VERSION 5.8 ;
BUSBITCHARS "[]" ;
DIVIDERCHAR "/" ;
UNITS
    DATABASE MICRONS 1000 ;
END UNITS

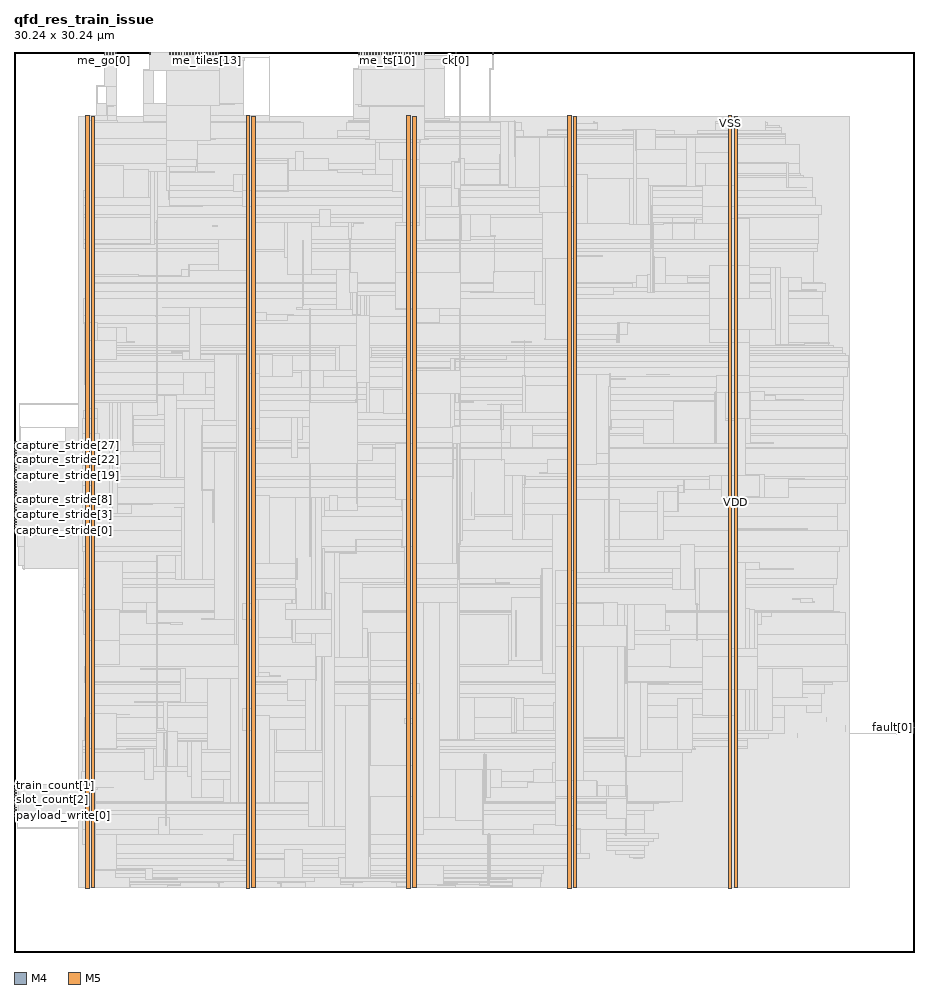
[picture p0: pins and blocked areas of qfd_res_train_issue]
MACRO qfd_res_train_issue
  FOREIGN qfd_res_train_issue 0 0 ;
  CLASS BLOCK ;
  SIZE 30.24 BY 30.24 ;
  PIN capture_stride[0]
    DIRECTION OUTPUT ;
    USE SIGNAL ;
    PORT
      LAYER M4 ;
        RECT  0 14.16 0.084 14.184 ;
    END
  END capture_stride[0]
  PIN capture_stride[10]
    DIRECTION OUTPUT ;
    USE SIGNAL ;
    PORT
      LAYER M4 ;
        RECT  0 15.12 0.084 15.144 ;
    END
  END capture_stride[10]
  PIN capture_stride[11]
    DIRECTION OUTPUT ;
    USE SIGNAL ;
    PORT
      LAYER M4 ;
        RECT  0 15.216 0.084 15.24 ;
    END
  END capture_stride[11]
  PIN capture_stride[12]
    DIRECTION OUTPUT ;
    USE SIGNAL ;
    PORT
      LAYER M4 ;
        RECT  0 15.312 0.084 15.336 ;
    END
  END capture_stride[12]
  PIN capture_stride[13]
    DIRECTION OUTPUT ;
    USE SIGNAL ;
    PORT
      LAYER M4 ;
        RECT  0 15.408 0.084 15.432 ;
    END
  END capture_stride[13]
  PIN capture_stride[14]
    DIRECTION OUTPUT ;
    USE SIGNAL ;
    PORT
      LAYER M4 ;
        RECT  0 15.504 0.084 15.528 ;
    END
  END capture_stride[14]
  PIN capture_stride[15]
    DIRECTION OUTPUT ;
    USE SIGNAL ;
    PORT
      LAYER M4 ;
        RECT  0 15.6 0.084 15.624 ;
    END
  END capture_stride[15]
  PIN capture_stride[16]
    DIRECTION OUTPUT ;
    USE SIGNAL ;
    PORT
      LAYER M4 ;
        RECT  0 15.696 0.084 15.72 ;
    END
  END capture_stride[16]
  PIN capture_stride[17]
    DIRECTION OUTPUT ;
    USE SIGNAL ;
    PORT
      LAYER M4 ;
        RECT  0 15.792 0.084 15.816 ;
    END
  END capture_stride[17]
  PIN capture_stride[18]
    DIRECTION OUTPUT ;
    USE SIGNAL ;
    PORT
      LAYER M4 ;
        RECT  0 15.888 0.084 15.912 ;
    END
  END capture_stride[18]
  PIN capture_stride[19]
    DIRECTION OUTPUT ;
    USE SIGNAL ;
    PORT
      LAYER M4 ;
        RECT  0 15.984 0.084 16.008 ;
    END
  END capture_stride[19]
  PIN capture_stride[1]
    DIRECTION OUTPUT ;
    USE SIGNAL ;
    PORT
      LAYER M4 ;
        RECT  0 14.256 0.084 14.28 ;
    END
  END capture_stride[1]
  PIN capture_stride[20]
    DIRECTION OUTPUT ;
    USE SIGNAL ;
    PORT
      LAYER M4 ;
        RECT  0 16.08 0.084 16.104 ;
    END
  END capture_stride[20]
  PIN capture_stride[21]
    DIRECTION OUTPUT ;
    USE SIGNAL ;
    PORT
      LAYER M4 ;
        RECT  0 16.176 0.084 16.2 ;
    END
  END capture_stride[21]
  PIN capture_stride[22]
    DIRECTION OUTPUT ;
    USE SIGNAL ;
    PORT
      LAYER M4 ;
        RECT  0 16.272 0.084 16.296 ;
    END
  END capture_stride[22]
  PIN capture_stride[23]
    DIRECTION OUTPUT ;
    USE SIGNAL ;
    PORT
      LAYER M4 ;
        RECT  0 16.368 0.084 16.392 ;
    END
  END capture_stride[23]
  PIN capture_stride[24]
    DIRECTION OUTPUT ;
    USE SIGNAL ;
    PORT
      LAYER M4 ;
        RECT  0 16.464 0.084 16.488 ;
    END
  END capture_stride[24]
  PIN capture_stride[25]
    DIRECTION OUTPUT ;
    USE SIGNAL ;
    PORT
      LAYER M4 ;
        RECT  0 16.56 0.084 16.584 ;
    END
  END capture_stride[25]
  PIN capture_stride[26]
    DIRECTION OUTPUT ;
    USE SIGNAL ;
    PORT
      LAYER M4 ;
        RECT  0 16.656 0.084 16.68 ;
    END
  END capture_stride[26]
  PIN capture_stride[27]
    DIRECTION OUTPUT ;
    USE SIGNAL ;
    PORT
      LAYER M4 ;
        RECT  0 16.752 0.084 16.776 ;
    END
  END capture_stride[27]
  PIN capture_stride[28]
    DIRECTION OUTPUT ;
    USE SIGNAL ;
    PORT
      LAYER M4 ;
        RECT  0 16.848 0.084 16.872 ;
    END
  END capture_stride[28]
  PIN capture_stride[29]
    DIRECTION OUTPUT ;
    USE SIGNAL ;
    PORT
      LAYER M4 ;
        RECT  0 16.944 0.084 16.968 ;
    END
  END capture_stride[29]
  PIN capture_stride[2]
    DIRECTION OUTPUT ;
    USE SIGNAL ;
    PORT
      LAYER M4 ;
        RECT  0 14.352 0.084 14.376 ;
    END
  END capture_stride[2]
  PIN capture_stride[30]
    DIRECTION OUTPUT ;
    USE SIGNAL ;
    PORT
      LAYER M4 ;
        RECT  0 17.04 0.084 17.064 ;
    END
  END capture_stride[30]
  PIN capture_stride[31]
    DIRECTION OUTPUT ;
    USE SIGNAL ;
    PORT
      LAYER M4 ;
        RECT  0 17.136 0.084 17.16 ;
    END
  END capture_stride[31]
  PIN capture_stride[3]
    DIRECTION OUTPUT ;
    USE SIGNAL ;
    PORT
      LAYER M4 ;
        RECT  0 14.448 0.084 14.472 ;
    END
  END capture_stride[3]
  PIN capture_stride[4]
    DIRECTION OUTPUT ;
    USE SIGNAL ;
    PORT
      LAYER M4 ;
        RECT  0 14.544 0.084 14.568 ;
    END
  END capture_stride[4]
  PIN capture_stride[5]
    DIRECTION OUTPUT ;
    USE SIGNAL ;
    PORT
      LAYER M4 ;
        RECT  0 14.64 0.084 14.664 ;
    END
  END capture_stride[5]
  PIN capture_stride[6]
    DIRECTION OUTPUT ;
    USE SIGNAL ;
    PORT
      LAYER M4 ;
        RECT  0 14.736 0.084 14.76 ;
    END
  END capture_stride[6]
  PIN capture_stride[7]
    DIRECTION OUTPUT ;
    USE SIGNAL ;
    PORT
      LAYER M4 ;
        RECT  0 14.832 0.084 14.856 ;
    END
  END capture_stride[7]
  PIN capture_stride[8]
    DIRECTION OUTPUT ;
    USE SIGNAL ;
    PORT
      LAYER M4 ;
        RECT  0 14.928 0.084 14.952 ;
    END
  END capture_stride[8]
  PIN capture_stride[9]
    DIRECTION OUTPUT ;
    USE SIGNAL ;
    PORT
      LAYER M4 ;
        RECT  0 15.024 0.084 15.048 ;
    END
  END capture_stride[9]
  PIN ck[0]
    DIRECTION INPUT ;
    USE SIGNAL ;
    PORT
      LAYER M5 ;
        RECT  14.832 30.156 14.856 30.24 ;
    END
  END ck[0]
  PIN fault[0]
    DIRECTION OUTPUT ;
    USE SIGNAL ;
    PORT
      LAYER M4 ;
        RECT  30.156 7.536 30.24 7.56 ;
    END
  END fault[0]
  PIN me_go[0]
    DIRECTION INPUT ;
    USE SIGNAL ;
    PORT
      LAYER M5 ;
        RECT  3.024 30.156 3.048 30.24 ;
    END
  END me_go[0]
  PIN me_oen[0]
    DIRECTION INPUT ;
    USE SIGNAL ;
    PORT
      LAYER M5 ;
        RECT  4.56 30.156 4.584 30.24 ;
    END
  END me_oen[0]
  PIN me_split[0]
    DIRECTION INPUT ;
    USE SIGNAL ;
    PORT
      LAYER M5 ;
        RECT  3.12 30.156 3.144 30.24 ;
    END
  END me_split[0]
  PIN me_split[1]
    DIRECTION INPUT ;
    USE SIGNAL ;
    PORT
      LAYER M5 ;
        RECT  3.216 30.156 3.24 30.24 ;
    END
  END me_split[1]
  PIN me_split[2]
    DIRECTION INPUT ;
    USE SIGNAL ;
    PORT
      LAYER M5 ;
        RECT  3.312 30.156 3.336 30.24 ;
    END
  END me_split[2]
  PIN me_split[3]
    DIRECTION INPUT ;
    USE SIGNAL ;
    PORT
      LAYER M5 ;
        RECT  3.408 30.156 3.432 30.24 ;
    END
  END me_split[3]
  PIN me_tiles[0]
    DIRECTION INPUT ;
    USE SIGNAL ;
    PORT
      LAYER M5 ;
        RECT  5.232 30.156 5.256 30.24 ;
    END
  END me_tiles[0]
  PIN me_tiles[10]
    DIRECTION INPUT ;
    USE SIGNAL ;
    PORT
      LAYER M5 ;
        RECT  6.192 30.156 6.216 30.24 ;
    END
  END me_tiles[10]
  PIN me_tiles[11]
    DIRECTION INPUT ;
    USE SIGNAL ;
    PORT
      LAYER M5 ;
        RECT  6.288 30.156 6.312 30.24 ;
    END
  END me_tiles[11]
  PIN me_tiles[12]
    DIRECTION INPUT ;
    USE SIGNAL ;
    PORT
      LAYER M5 ;
        RECT  6.384 30.156 6.408 30.24 ;
    END
  END me_tiles[12]
  PIN me_tiles[13]
    DIRECTION INPUT ;
    USE SIGNAL ;
    PORT
      LAYER M5 ;
        RECT  6.48 30.156 6.504 30.24 ;
    END
  END me_tiles[13]
  PIN me_tiles[14]
    DIRECTION INPUT ;
    USE SIGNAL ;
    PORT
      LAYER M5 ;
        RECT  6.576 30.156 6.6 30.24 ;
    END
  END me_tiles[14]
  PIN me_tiles[15]
    DIRECTION INPUT ;
    USE SIGNAL ;
    PORT
      LAYER M5 ;
        RECT  6.672 30.156 6.696 30.24 ;
    END
  END me_tiles[15]
  PIN me_tiles[16]
    DIRECTION INPUT ;
    USE SIGNAL ;
    PORT
      LAYER M5 ;
        RECT  6.768 30.156 6.792 30.24 ;
    END
  END me_tiles[16]
  PIN me_tiles[17]
    DIRECTION INPUT ;
    USE SIGNAL ;
    PORT
      LAYER M5 ;
        RECT  6.864 30.156 6.888 30.24 ;
    END
  END me_tiles[17]
  PIN me_tiles[1]
    DIRECTION INPUT ;
    USE SIGNAL ;
    PORT
      LAYER M5 ;
        RECT  5.328 30.156 5.352 30.24 ;
    END
  END me_tiles[1]
  PIN me_tiles[2]
    DIRECTION INPUT ;
    USE SIGNAL ;
    PORT
      LAYER M5 ;
        RECT  5.424 30.156 5.448 30.24 ;
    END
  END me_tiles[2]
  PIN me_tiles[3]
    DIRECTION INPUT ;
    USE SIGNAL ;
    PORT
      LAYER M5 ;
        RECT  5.52 30.156 5.544 30.24 ;
    END
  END me_tiles[3]
  PIN me_tiles[4]
    DIRECTION INPUT ;
    USE SIGNAL ;
    PORT
      LAYER M5 ;
        RECT  5.616 30.156 5.64 30.24 ;
    END
  END me_tiles[4]
  PIN me_tiles[5]
    DIRECTION INPUT ;
    USE SIGNAL ;
    PORT
      LAYER M5 ;
        RECT  5.712 30.156 5.736 30.24 ;
    END
  END me_tiles[5]
  PIN me_tiles[6]
    DIRECTION INPUT ;
    USE SIGNAL ;
    PORT
      LAYER M5 ;
        RECT  5.808 30.156 5.832 30.24 ;
    END
  END me_tiles[6]
  PIN me_tiles[7]
    DIRECTION INPUT ;
    USE SIGNAL ;
    PORT
      LAYER M5 ;
        RECT  5.904 30.156 5.928 30.24 ;
    END
  END me_tiles[7]
  PIN me_tiles[8]
    DIRECTION INPUT ;
    USE SIGNAL ;
    PORT
      LAYER M5 ;
        RECT  6 30.156 6.024 30.24 ;
    END
  END me_tiles[8]
  PIN me_tiles[9]
    DIRECTION INPUT ;
    USE SIGNAL ;
    PORT
      LAYER M5 ;
        RECT  6.096 30.156 6.12 30.24 ;
    END
  END me_tiles[9]
  PIN me_ts[0]
    DIRECTION INPUT ;
    USE SIGNAL ;
    PORT
      LAYER M5 ;
        RECT  11.568 30.156 11.592 30.24 ;
    END
  END me_ts[0]
  PIN me_ts[10]
    DIRECTION INPUT ;
    USE SIGNAL ;
    PORT
      LAYER M5 ;
        RECT  12.528 30.156 12.552 30.24 ;
    END
  END me_ts[10]
  PIN me_ts[11]
    DIRECTION INPUT ;
    USE SIGNAL ;
    PORT
      LAYER M5 ;
        RECT  12.624 30.156 12.648 30.24 ;
    END
  END me_ts[11]
  PIN me_ts[12]
    DIRECTION INPUT ;
    USE SIGNAL ;
    PORT
      LAYER M5 ;
        RECT  12.72 30.156 12.744 30.24 ;
    END
  END me_ts[12]
  PIN me_ts[13]
    DIRECTION INPUT ;
    USE SIGNAL ;
    PORT
      LAYER M5 ;
        RECT  12.816 30.156 12.84 30.24 ;
    END
  END me_ts[13]
  PIN me_ts[14]
    DIRECTION INPUT ;
    USE SIGNAL ;
    PORT
      LAYER M5 ;
        RECT  12.912 30.156 12.936 30.24 ;
    END
  END me_ts[14]
  PIN me_ts[15]
    DIRECTION INPUT ;
    USE SIGNAL ;
    PORT
      LAYER M5 ;
        RECT  13.008 30.156 13.032 30.24 ;
    END
  END me_ts[15]
  PIN me_ts[16]
    DIRECTION INPUT ;
    USE SIGNAL ;
    PORT
      LAYER M5 ;
        RECT  13.104 30.156 13.128 30.24 ;
    END
  END me_ts[16]
  PIN me_ts[17]
    DIRECTION INPUT ;
    USE SIGNAL ;
    PORT
      LAYER M5 ;
        RECT  13.2 30.156 13.224 30.24 ;
    END
  END me_ts[17]
  PIN me_ts[18]
    DIRECTION INPUT ;
    USE SIGNAL ;
    PORT
      LAYER M5 ;
        RECT  13.296 30.156 13.32 30.24 ;
    END
  END me_ts[18]
  PIN me_ts[19]
    DIRECTION INPUT ;
    USE SIGNAL ;
    PORT
      LAYER M5 ;
        RECT  13.392 30.156 13.416 30.24 ;
    END
  END me_ts[19]
  PIN me_ts[1]
    DIRECTION INPUT ;
    USE SIGNAL ;
    PORT
      LAYER M5 ;
        RECT  11.664 30.156 11.688 30.24 ;
    END
  END me_ts[1]
  PIN me_ts[20]
    DIRECTION INPUT ;
    USE SIGNAL ;
    PORT
      LAYER M5 ;
        RECT  13.488 30.156 13.512 30.24 ;
    END
  END me_ts[20]
  PIN me_ts[21]
    DIRECTION INPUT ;
    USE SIGNAL ;
    PORT
      LAYER M5 ;
        RECT  13.584 30.156 13.608 30.24 ;
    END
  END me_ts[21]
  PIN me_ts[22]
    DIRECTION INPUT ;
    USE SIGNAL ;
    PORT
      LAYER M5 ;
        RECT  13.68 30.156 13.704 30.24 ;
    END
  END me_ts[22]
  PIN me_ts[23]
    DIRECTION INPUT ;
    USE SIGNAL ;
    PORT
      LAYER M5 ;
        RECT  13.776 30.156 13.8 30.24 ;
    END
  END me_ts[23]
  PIN me_ts[2]
    DIRECTION INPUT ;
    USE SIGNAL ;
    PORT
      LAYER M5 ;
        RECT  11.76 30.156 11.784 30.24 ;
    END
  END me_ts[2]
  PIN me_ts[3]
    DIRECTION INPUT ;
    USE SIGNAL ;
    PORT
      LAYER M5 ;
        RECT  11.856 30.156 11.88 30.24 ;
    END
  END me_ts[3]
  PIN me_ts[4]
    DIRECTION INPUT ;
    USE SIGNAL ;
    PORT
      LAYER M5 ;
        RECT  11.952 30.156 11.976 30.24 ;
    END
  END me_ts[4]
  PIN me_ts[5]
    DIRECTION INPUT ;
    USE SIGNAL ;
    PORT
      LAYER M5 ;
        RECT  12.048 30.156 12.072 30.24 ;
    END
  END me_ts[5]
  PIN me_ts[6]
    DIRECTION INPUT ;
    USE SIGNAL ;
    PORT
      LAYER M5 ;
        RECT  12.144 30.156 12.168 30.24 ;
    END
  END me_ts[6]
  PIN me_ts[7]
    DIRECTION INPUT ;
    USE SIGNAL ;
    PORT
      LAYER M5 ;
        RECT  12.24 30.156 12.264 30.24 ;
    END
  END me_ts[7]
  PIN me_ts[8]
    DIRECTION INPUT ;
    USE SIGNAL ;
    PORT
      LAYER M5 ;
        RECT  12.336 30.156 12.36 30.24 ;
    END
  END me_ts[8]
  PIN me_ts[9]
    DIRECTION INPUT ;
    USE SIGNAL ;
    PORT
      LAYER M5 ;
        RECT  12.432 30.156 12.456 30.24 ;
    END
  END me_ts[9]
  PIN payload_write[0]
    DIRECTION OUTPUT ;
    USE SIGNAL ;
    PORT
      LAYER M4 ;
        RECT  0 4.56 0.084 4.584 ;
    END
  END payload_write[0]
  PIN rst_n[0]
    DIRECTION INPUT ;
    USE SIGNAL ;
    PORT
      LAYER M5 ;
        RECT  16.08 30.156 16.104 30.24 ;
    END
  END rst_n[0]
  PIN slot_count[0]
    DIRECTION OUTPUT ;
    USE SIGNAL ;
    PORT
      LAYER M4 ;
        RECT  0 4.656 0.084 4.68 ;
    END
  END slot_count[0]
  PIN slot_count[1]
    DIRECTION OUTPUT ;
    USE SIGNAL ;
    PORT
      LAYER M4 ;
        RECT  0 4.752 0.084 4.776 ;
    END
  END slot_count[1]
  PIN slot_count[2]
    DIRECTION OUTPUT ;
    USE SIGNAL ;
    PORT
      LAYER M4 ;
        RECT  0 4.848 0.084 4.872 ;
    END
  END slot_count[2]
  PIN slot_count[3]
    DIRECTION OUTPUT ;
    USE SIGNAL ;
    PORT
      LAYER M4 ;
        RECT  0 4.944 0.084 4.968 ;
    END
  END slot_count[3]
  PIN tag_last[0]
    DIRECTION INPUT ;
    USE SIGNAL ;
    PORT
      LAYER M4 ;
        RECT  0 5.04 0.084 5.064 ;
    END
  END tag_last[0]
  PIN tag_v[0]
    DIRECTION INPUT ;
    USE SIGNAL ;
    PORT
      LAYER M4 ;
        RECT  0 5.136 0.084 5.16 ;
    END
  END tag_v[0]
  PIN train_count[0]
    DIRECTION OUTPUT ;
    USE SIGNAL ;
    PORT
      LAYER M4 ;
        RECT  0 5.232 0.084 5.256 ;
    END
  END train_count[0]
  PIN train_count[1]
    DIRECTION OUTPUT ;
    USE SIGNAL ;
    PORT
      LAYER M4 ;
        RECT  0 5.328 0.084 5.352 ;
    END
  END train_count[1]
  PIN train_count[2]
    DIRECTION OUTPUT ;
    USE SIGNAL ;
    PORT
      LAYER M4 ;
        RECT  0 5.424 0.084 5.448 ;
    END
  END train_count[2]
  PIN train_count[3]
    DIRECTION OUTPUT ;
    USE SIGNAL ;
    PORT
      LAYER M4 ;
        RECT  0 5.52 0.084 5.544 ;
    END
  END train_count[3]
  PIN train_start[0]
    DIRECTION OUTPUT ;
    USE SIGNAL ;
    PORT
      LAYER M4 ;
        RECT  0 5.616 0.084 5.64 ;
    END
  END train_start[0]
  PIN VDD
    DIRECTION INOUT ;
    USE POWER ;
    PORT
      LAYER M5 ;
        RECT  24.192 2.151 24.312 28.089 ;
        RECT  18.792 2.151 18.912 28.089 ;
        RECT  13.392 2.151 13.512 28.089 ;
        RECT  7.992 2.151 8.112 28.089 ;
        RECT  2.592 2.151 2.712 28.089 ;
    END
  END VDD
  PIN VSS
    DIRECTION INOUT ;
    USE GROUND ;
    PORT
      LAYER M5 ;
        RECT  24 2.137 24.12 28.103 ;
        RECT  18.6 2.137 18.72 28.103 ;
        RECT  13.2 2.137 13.32 28.103 ;
        RECT  7.8 2.137 7.92 28.103 ;
        RECT  2.4 2.137 2.52 28.103 ;
    END
  END VSS
  OBS
    LAYER RVTN ;
     RECT  2.16 2.16 28.08 2.295 ;
     RECT  2.16 2.565 28.08 2.835 ;
     RECT  2.16 3.105 28.08 3.375 ;
     RECT  2.16 3.645 28.08 3.915 ;
     RECT  2.16 4.185 28.08 4.455 ;
     RECT  2.16 4.725 28.08 4.995 ;
     RECT  2.16 5.265 28.08 5.535 ;
     RECT  2.16 5.805 28.08 6.075 ;
     RECT  2.16 6.345 28.08 6.615 ;
     RECT  2.16 6.885 28.08 7.155 ;
     RECT  2.16 7.425 28.08 7.695 ;
     RECT  2.16 7.965 28.08 8.235 ;
     RECT  2.16 8.505 28.08 8.775 ;
     RECT  2.16 9.045 28.08 9.315 ;
     RECT  2.16 9.585 28.08 9.855 ;
     RECT  2.16 10.125 28.08 10.395 ;
     RECT  2.16 10.665 28.08 10.935 ;
     RECT  2.16 11.205 28.08 11.475 ;
     RECT  2.16 11.745 28.08 12.015 ;
     RECT  2.16 12.285 28.08 12.555 ;
     RECT  2.16 12.825 28.08 13.095 ;
     RECT  2.16 13.365 28.08 13.635 ;
     RECT  2.16 13.905 28.08 14.175 ;
     RECT  2.16 14.445 28.08 14.715 ;
     RECT  2.16 14.985 28.08 15.255 ;
     RECT  2.16 15.525 28.08 15.795 ;
     RECT  2.16 16.065 28.08 16.335 ;
     RECT  2.16 16.605 28.08 16.875 ;
     RECT  2.16 17.145 28.08 17.415 ;
     RECT  2.16 17.685 28.08 17.955 ;
     RECT  2.16 18.225 28.08 18.495 ;
     RECT  2.16 18.765 28.08 19.035 ;
     RECT  2.16 19.305 28.08 19.575 ;
     RECT  2.16 19.845 28.08 20.115 ;
     RECT  2.16 20.385 28.08 20.655 ;
     RECT  2.16 20.925 28.08 21.195 ;
     RECT  2.16 21.465 28.08 21.735 ;
     RECT  2.16 22.005 28.08 22.275 ;
     RECT  2.16 22.545 28.08 22.815 ;
     RECT  2.16 23.085 28.08 23.355 ;
     RECT  2.16 23.625 28.08 23.895 ;
     RECT  2.16 24.165 28.08 24.435 ;
     RECT  2.16 24.705 28.08 24.975 ;
     RECT  2.16 25.245 28.08 25.515 ;
     RECT  2.16 25.785 28.08 26.055 ;
     RECT  2.16 26.325 28.08 26.595 ;
     RECT  2.16 26.865 28.08 27.135 ;
     RECT  2.16 27.405 28.08 27.675 ;
     RECT  2.16 27.945 28.08 28.08 ;
    LAYER RVTP ;
     RECT  2.16 2.295 28.08 2.565 ;
     RECT  2.16 2.835 28.08 3.105 ;
     RECT  2.16 3.375 28.08 3.645 ;
     RECT  2.16 3.915 28.08 4.185 ;
     RECT  2.16 4.455 28.08 4.725 ;
     RECT  2.16 4.995 28.08 5.265 ;
     RECT  2.16 5.535 28.08 5.805 ;
     RECT  2.16 6.075 28.08 6.345 ;
     RECT  2.16 6.615 28.08 6.885 ;
     RECT  2.16 7.155 28.08 7.425 ;
     RECT  2.16 7.695 28.08 7.965 ;
     RECT  2.16 8.235 28.08 8.505 ;
     RECT  2.16 8.775 28.08 9.045 ;
     RECT  2.16 9.315 28.08 9.585 ;
     RECT  2.16 9.855 28.08 10.125 ;
     RECT  2.16 10.395 28.08 10.665 ;
     RECT  2.16 10.935 28.08 11.205 ;
     RECT  2.16 11.475 28.08 11.745 ;
     RECT  2.16 12.015 28.08 12.285 ;
     RECT  2.16 12.555 28.08 12.825 ;
     RECT  2.16 13.095 28.08 13.365 ;
     RECT  2.16 13.635 28.08 13.905 ;
     RECT  2.16 14.175 28.08 14.445 ;
     RECT  2.16 14.715 28.08 14.985 ;
     RECT  2.16 15.255 28.08 15.525 ;
     RECT  2.16 15.795 28.08 16.065 ;
     RECT  2.16 16.335 28.08 16.605 ;
     RECT  2.16 16.875 28.08 17.145 ;
     RECT  2.16 17.415 28.08 17.685 ;
     RECT  2.16 17.955 28.08 18.225 ;
     RECT  2.16 18.495 28.08 18.765 ;
     RECT  2.16 19.035 28.08 19.305 ;
     RECT  2.16 19.575 28.08 19.845 ;
     RECT  2.16 20.115 28.08 20.385 ;
     RECT  2.16 20.655 28.08 20.925 ;
     RECT  2.16 21.195 28.08 21.465 ;
     RECT  2.16 21.735 28.08 22.005 ;
     RECT  2.16 22.275 28.08 22.545 ;
     RECT  2.16 22.815 28.08 23.085 ;
     RECT  2.16 23.355 28.08 23.625 ;
     RECT  2.16 23.895 28.08 24.165 ;
     RECT  2.16 24.435 28.08 24.705 ;
     RECT  2.16 24.975 28.08 25.245 ;
     RECT  2.16 25.515 28.08 25.785 ;
     RECT  2.16 26.055 28.08 26.325 ;
     RECT  2.16 26.595 28.08 26.865 ;
     RECT  2.16 27.135 28.08 27.405 ;
     RECT  2.16 27.675 28.08 27.945 ;
    LAYER M1 ;
     RECT  2.16 2.151 28.08 28.089 ;
    LAYER M2 ;
     RECT  0.103 13.644 0.139 13.662 ;
     RECT  0.139 12.996 0.175 13.662 ;
     RECT  0.103 14.796 0.175 15.354 ;
     RECT  0.175 12.996 0.283 14.004 ;
     RECT  0.283 12.906 0.319 14.004 ;
     RECT  0.211 17.622 1.723 17.64 ;
     RECT  0.103 4.158 2.16 4.176 ;
     RECT  0.319 12.87 2.16 14.004 ;
     RECT  0.175 14.796 2.16 15.858 ;
     RECT  1.723 16.884 2.16 17.64 ;
     RECT  0.175 18.396 2.16 18.414 ;
     RECT  2.16 2.151 28.08 28.089 ;
     RECT  28.08 7.326 29.687 7.344 ;
    LAYER M3 ;
     RECT  13.215 2.143 13.305 2.191 ;
     RECT  5.148 2.191 5.166 2.227 ;
     RECT  14.832 2.191 14.85 2.251 ;
     RECT  16.02 2.191 16.758 2.251 ;
     RECT  3.888 2.191 3.906 2.263 ;
     RECT  5.148 2.227 5.598 2.263 ;
     RECT  11.376 2.191 11.394 2.263 ;
     RECT  6.876 2.191 6.894 2.299 ;
     RECT  8.964 2.191 8.982 2.299 ;
     RECT  14.22 2.251 14.85 2.299 ;
     RECT  3.888 2.263 5.598 2.335 ;
     RECT  6.84 2.299 6.894 2.335 ;
     RECT  8.856 2.299 8.982 2.335 ;
     RECT  9.792 2.191 9.81 2.335 ;
     RECT  10.98 2.263 11.394 2.335 ;
     RECT  12.852 2.191 13.305 2.335 ;
     RECT  14.22 2.299 14.886 2.335 ;
     RECT  15.624 2.251 16.758 2.335 ;
     RECT  3.888 2.335 7.038 2.371 ;
     RECT  7.815 2.143 7.905 2.371 ;
     RECT  8.856 2.335 9.81 2.371 ;
     RECT  10.98 2.335 11.718 2.371 ;
     RECT  12.672 2.335 13.41 2.371 ;
     RECT  14.22 2.335 16.758 2.371 ;
     RECT  17.676 2.191 17.694 2.371 ;
     RECT  2.415 2.143 2.505 2.413 ;
     RECT  18.615 2.143 18.705 2.413 ;
     RECT  24.015 2.143 24.105 2.413 ;
     RECT  10.98 2.371 16.758 2.461 ;
     RECT  17.676 2.371 17.73 2.461 ;
     RECT  3.888 2.371 10.098 2.497 ;
     RECT  10.98 2.461 17.73 2.497 ;
     RECT  3.42 2.497 17.73 2.641 ;
     RECT  2.415 2.413 2.697 2.731 ;
     RECT  3.42 2.641 17.802 2.731 ;
     RECT  2.415 2.731 17.802 2.911 ;
     RECT  18.615 2.413 18.897 2.911 ;
     RECT  2.415 2.911 18.897 3.145 ;
     RECT  20.808 3.145 21.114 3.181 ;
     RECT  20.664 3.181 21.186 3.271 ;
     RECT  2.415 3.145 19.35 3.299 ;
     RECT  20.196 3.271 21.186 3.415 ;
     RECT  19.908 3.415 21.186 3.577 ;
     RECT  2.415 3.299 19.026 3.613 ;
     RECT  19.908 3.577 21.33 3.721 ;
     RECT  19.908 3.721 21.474 3.811 ;
     RECT  19.908 3.811 21.654 3.983 ;
     RECT  2.304 3.613 19.026 4.117 ;
     RECT  19.908 3.983 21.186 4.117 ;
     RECT  0.108 4.153 0.126 4.589 ;
     RECT  2.304 4.117 21.186 4.621 ;
     RECT  2.268 4.621 21.186 4.765 ;
     RECT  2.268 4.765 21.474 4.999 ;
     RECT  2.268 4.999 21.654 5.035 ;
     RECT  2.268 5.035 22.014 5.071 ;
     RECT  0.144 5.323 0.162 5.501 ;
     RECT  2.268 5.071 22.446 6.071 ;
     RECT  2.304 6.071 22.446 6.691 ;
     RECT  2.304 6.691 22.77 6.811 ;
     RECT  24.015 2.413 24.297 6.853 ;
     RECT  2.304 6.811 22.878 6.889 ;
     RECT  24.015 6.853 24.642 6.889 ;
     RECT  2.304 6.889 24.642 7.115 ;
     RECT  2.376 7.115 24.642 7.159 ;
     RECT  26.316 7.195 26.334 7.349 ;
     RECT  2.376 7.159 25.362 7.357 ;
     RECT  29.664 7.321 29.682 7.565 ;
     RECT  27.936 7.393 27.954 7.619 ;
     RECT  2.376 7.357 25.902 7.889 ;
     RECT  27.288 7.735 27.306 7.889 ;
     RECT  2.415 7.889 25.902 8.275 ;
     RECT  26.64 8.041 27.126 8.275 ;
     RECT  2.415 8.275 27.126 8.671 ;
     RECT  2.415 8.671 27.234 8.977 ;
     RECT  2.415 8.977 27.486 9.049 ;
     RECT  2.376 9.049 27.486 9.085 ;
     RECT  2.376 9.085 27.99 9.581 ;
     RECT  2.415 9.581 27.99 10.319 ;
     RECT  2.415 10.319 27.954 10.669 ;
     RECT  2.34 10.669 27.954 11.399 ;
     RECT  2.34 11.399 27.738 11.435 ;
     RECT  2.34 11.435 27.522 11.479 ;
     RECT  2.304 11.479 27.522 12.245 ;
     RECT  2.34 12.245 27.522 12.361 ;
     RECT  2.34 12.361 27.63 12.559 ;
     RECT  0.324 12.865 0.342 12.901 ;
     RECT  0.288 12.901 0.342 12.991 ;
     RECT  2.34 12.559 27.666 13.441 ;
     RECT  0.144 12.991 0.342 13.639 ;
     RECT  2.304 13.441 27.738 13.639 ;
     RECT  2.304 13.639 27.99 14.171 ;
     RECT  2.304 14.171 27.666 14.639 ;
     RECT  0.108 13.639 0.342 14.953 ;
     RECT  0.108 14.953 0.378 15.053 ;
     RECT  2.34 14.639 27.666 15.061 ;
     RECT  0.108 15.053 0.306 15.245 ;
     RECT  0.108 15.245 0.198 15.437 ;
     RECT  2.34 15.061 27.954 15.595 ;
     RECT  2.304 15.595 27.954 15.871 ;
     RECT  2.304 15.871 27.99 15.989 ;
     RECT  0.18 15.437 0.198 16.171 ;
     RECT  2.304 15.989 27.954 16.411 ;
     RECT  1.728 16.411 27.954 16.907 ;
     RECT  2.268 16.907 27.954 16.915 ;
     RECT  2.268 16.915 27.99 16.943 ;
     RECT  0.18 16.171 0.342 17.069 ;
     RECT  2.268 16.943 16.686 17.105 ;
     RECT  17.424 16.943 27.99 17.339 ;
     RECT  17.424 17.339 27.954 17.411 ;
     RECT  0.18 17.069 0.234 17.645 ;
     RECT  2.304 17.105 16.686 17.689 ;
     RECT  17.424 17.411 27.846 17.689 ;
     RECT  2.304 17.689 27.846 17.879 ;
     RECT  2.34 17.879 27.846 18.185 ;
     RECT  0.18 17.645 0.198 18.419 ;
     RECT  2.415 18.185 27.846 18.535 ;
     RECT  2.415 18.535 27.882 18.725 ;
     RECT  6.444 18.725 27.882 18.959 ;
     RECT  2.415 18.725 5.706 19.075 ;
     RECT  10.404 18.959 27.882 19.345 ;
     RECT  2.376 19.075 5.706 19.471 ;
     RECT  6.444 18.959 9.666 19.471 ;
     RECT  10.404 19.345 27.99 19.651 ;
     RECT  2.376 19.471 9.666 19.849 ;
     RECT  10.404 19.651 28.026 19.849 ;
     RECT  2.376 19.849 28.026 20.039 ;
     RECT  2.376 20.039 27.954 20.111 ;
     RECT  2.376 20.111 27.846 20.219 ;
     RECT  2.415 20.219 27.846 20.309 ;
     RECT  2.415 20.309 27.522 20.381 ;
     RECT  2.415 20.381 27.378 21.115 ;
     RECT  2.34 21.115 27.378 21.389 ;
     RECT  2.34 21.389 27.162 21.965 ;
     RECT  2.415 21.965 27.162 22.207 ;
     RECT  2.415 22.207 27.27 22.469 ;
     RECT  2.415 22.469 27.162 22.505 ;
     RECT  2.415 22.505 26.874 23.521 ;
     RECT  2.415 23.521 26.982 23.629 ;
     RECT  2.34 23.629 26.982 23.791 ;
     RECT  2.34 23.791 27.018 23.927 ;
     RECT  2.34 23.927 22.122 24.673 ;
     RECT  22.86 23.927 27.018 24.673 ;
     RECT  2.34 24.673 27.018 24.781 ;
     RECT  2.34 24.781 27.126 25.079 ;
     RECT  2.34 25.079 26.946 25.349 ;
     RECT  2.34 25.349 26.838 25.583 ;
     RECT  2.415 25.583 23.274 25.745 ;
     RECT  24.015 25.583 26.838 26.015 ;
     RECT  24.015 26.015 26.514 26.087 ;
     RECT  24.015 26.087 26.442 26.159 ;
     RECT  2.415 25.745 23.238 26.491 ;
     RECT  24.015 26.159 26.406 26.491 ;
     RECT  2.415 26.491 26.406 27.131 ;
     RECT  2.415 27.131 25.938 27.329 ;
     RECT  10.872 27.329 25.938 27.389 ;
     RECT  17.928 27.389 25.938 27.473 ;
     RECT  22.968 27.473 25.938 27.509 ;
     RECT  10.872 27.389 17.118 27.599 ;
     RECT  17.928 27.473 22.194 27.599 ;
     RECT  22.968 27.509 25.794 27.599 ;
     RECT  17.928 27.599 19.602 27.635 ;
     RECT  20.448 27.599 20.466 27.635 ;
     RECT  21.528 27.599 21.546 27.635 ;
     RECT  25.236 27.599 25.794 27.707 ;
     RECT  25.236 27.707 25.722 27.779 ;
     RECT  18.615 27.635 19.602 27.827 ;
     RECT  23.58 27.599 24.297 27.827 ;
     RECT  2.415 27.329 9.738 27.869 ;
     RECT  11.16 27.599 17.046 27.869 ;
     RECT  19.476 27.827 19.602 27.869 ;
     RECT  25.236 27.779 25.326 27.869 ;
     RECT  4.356 27.869 9.63 27.905 ;
     RECT  11.232 27.869 16.47 27.905 ;
     RECT  19.476 27.869 19.494 27.905 ;
     RECT  23.58 27.827 24.105 27.905 ;
     RECT  25.236 27.869 25.254 27.905 ;
     RECT  15.372 27.905 16.47 27.917 ;
     RECT  2.415 27.869 3.474 27.941 ;
     RECT  11.232 27.905 14.634 27.941 ;
     RECT  11.412 27.941 14.634 28.013 ;
     RECT  2.415 27.941 3.438 28.097 ;
     RECT  4.356 27.905 8.586 28.097 ;
     RECT  18.615 27.827 18.705 28.097 ;
     RECT  24.015 27.905 24.105 28.097 ;
     RECT  2.772 28.097 3.438 28.493 ;
     RECT  4.356 28.097 7.722 28.493 ;
     RECT  2.772 28.493 2.79 29.117 ;
     RECT  4.356 28.493 4.698 29.645 ;
     RECT  11.412 28.013 14.454 29.693 ;
     RECT  15.984 27.917 16.002 29.693 ;
     RECT  5.724 28.493 7.722 29.981 ;
     RECT  5.724 29.981 7.074 30.029 ;
     RECT  12.564 29.693 14.454 30.029 ;
     RECT  5.724 30.029 6.318 30.077 ;
     RECT  8.568 28.097 8.586 30.077 ;
     RECT  13.104 30.029 13.914 30.077 ;
     RECT  5.724 30.077 6.102 30.125 ;
     RECT  7.056 30.029 7.074 30.125 ;
     RECT  13.104 30.077 13.122 30.125 ;
     RECT  13.896 30.077 13.914 30.125 ;
    LAYER M4 ;
     RECT  0.06 4.56 0.137 5.64 ;
     RECT  0.06 14.16 2.293 17.16 ;
     RECT  2.329 21.12 2.365 21.144 ;
     RECT  0.137 4.656 2.408 5.64 ;
     RECT  2.329 12 2.408 12.024 ;
     RECT  2.293 14.16 2.408 17.928 ;
     RECT  2.365 20.16 2.408 21.144 ;
     RECT  2.408 2.148 2.512 28.092 ;
     RECT  2.512 2.418 2.704 28.092 ;
     RECT  2.704 2.784 2.729 5.544 ;
     RECT  2.729 5.472 2.801 5.544 ;
     RECT  2.704 19.92 2.819 21.144 ;
     RECT  2.761 29.088 3.059 29.112 ;
     RECT  2.704 27.936 3.155 28.092 ;
     RECT  2.704 14.16 3.197 18.456 ;
     RECT  3.197 14.64 3.305 18.456 ;
     RECT  2.801 5.52 3.341 5.544 ;
     RECT  3.157 28.416 3.349 28.488 ;
     RECT  2.704 6.864 3.443 7.992 ;
     RECT  2.819 19.92 3.443 21 ;
     RECT  2.729 2.784 3.449 3.96 ;
     RECT  3.349 28.464 3.449 28.488 ;
     RECT  3.443 6.864 3.485 6.888 ;
     RECT  3.305 14.736 3.485 18.456 ;
     RECT  2.704 9.648 3.539 10.488 ;
     RECT  3.485 16.08 3.593 18.456 ;
     RECT  2.704 11.472 3.629 13.128 ;
     RECT  2.704 25.344 3.665 26.424 ;
     RECT  3.443 20.496 3.773 21 ;
     RECT  3.443 7.968 3.881 7.992 ;
     RECT  3.485 14.736 3.953 15.048 ;
     RECT  3.593 16.8 4.019 18.456 ;
     RECT  3.773 20.496 4.061 20.52 ;
     RECT  2.704 22.704 4.169 22.776 ;
     RECT  3.769 6.816 4.381 6.84 ;
     RECT  3.449 2.784 4.417 2.808 ;
     RECT  3.629 11.472 4.453 11.736 ;
     RECT  3.665 25.344 4.529 26.28 ;
     RECT  2.704 23.76 4.597 23.784 ;
     RECT  4.529 25.344 4.597 26.232 ;
     RECT  4.417 2.448 4.637 2.808 ;
     RECT  3.953 15.024 4.637 15.048 ;
     RECT  4.381 5.808 4.673 6.84 ;
     RECT  4.597 23.76 4.709 26.232 ;
     RECT  4.019 18.048 4.777 18.456 ;
     RECT  4.673 6.24 4.789 6.84 ;
     RECT  3.629 12.768 4.789 13.128 ;
     RECT  4.453 11.04 4.835 11.736 ;
     RECT  4.748 21.36 4.835 21.384 ;
     RECT  4.709 24.528 4.835 26.232 ;
     RECT  3.449 3.936 4.849 3.96 ;
     RECT  4.019 16.8 4.921 17.064 ;
     RECT  4.789 6.24 5.029 7.416 ;
     RECT  4.057 8.4 5.029 8.424 ;
     RECT  4.921 15.936 5.065 17.064 ;
     RECT  4.777 18.048 5.065 18.696 ;
     RECT  4.345 29.616 5.125 29.64 ;
     RECT  5.029 6.24 5.141 8.424 ;
     RECT  4.849 3.936 5.213 4.536 ;
     RECT  4.835 25.056 5.219 26.232 ;
     RECT  4.835 11.04 5.245 11.064 ;
     RECT  5.125 29.616 5.363 30.12 ;
     RECT  4.789 12.768 5.425 13.32 ;
     RECT  5.065 15.936 5.465 18.696 ;
     RECT  4.637 2.448 5.501 2.472 ;
     RECT  5.141 6.24 5.501 7.416 ;
     RECT  5.201 28.464 5.573 28.488 ;
     RECT  5.141 8.4 5.605 8.424 ;
     RECT  4.237 9.504 5.605 9.528 ;
     RECT  5.425 12.528 5.641 13.32 ;
     RECT  5.389 14.928 5.641 14.952 ;
     RECT  4.169 22.704 5.641 22.728 ;
     RECT  5.245 10.992 5.645 11.064 ;
     RECT  5.281 20.16 5.677 20.184 ;
     RECT  5.641 12.528 5.713 14.952 ;
     RECT  5.465 15.936 5.713 18.264 ;
     RECT  5.605 8.4 5.753 9.528 ;
     RECT  5.749 27.264 5.797 27.288 ;
     RECT  5.501 6.24 5.821 7.08 ;
     RECT  5.641 22.704 5.857 22.92 ;
     RECT  5.677 19.92 5.893 20.184 ;
     RECT  4.993 21.648 5.893 21.672 ;
     RECT  5.857 22.704 5.897 23.112 ;
     RECT  5.821 5.904 5.965 7.08 ;
     RECT  5.219 26.208 6.085 26.232 ;
     RECT  5.797 27.264 6.085 27.336 ;
     RECT  5.363 29.856 6.131 30.12 ;
     RECT  6.085 26.208 6.179 27.336 ;
     RECT  5.893 19.92 6.257 21.672 ;
     RECT  5.965 5.184 6.293 7.08 ;
     RECT  5.713 12.528 6.323 18.264 ;
     RECT  5.213 3.936 6.329 3.96 ;
     RECT  5.219 25.056 6.329 25.08 ;
     RECT  6.293 6.816 6.505 7.08 ;
     RECT  5.753 8.4 6.505 9.192 ;
     RECT  6.179 27.264 6.611 27.336 ;
     RECT  6.289 11.184 6.721 11.208 ;
     RECT  6.323 12.528 6.721 16.824 ;
     RECT  6.323 17.856 6.721 18.264 ;
     RECT  6.257 19.92 6.721 20.088 ;
     RECT  6.179 26.208 6.725 26.232 ;
     RECT  6.611 27.312 6.761 27.336 ;
     RECT  6.685 24.384 6.833 24.408 ;
     RECT  5.897 22.896 6.865 23.112 ;
     RECT  6.293 5.184 7.045 5.784 ;
     RECT  6.131 29.952 7.085 30.12 ;
     RECT  7.045 5.04 7.261 5.784 ;
     RECT  6.505 6.816 7.261 9.192 ;
     RECT  7.189 3.072 7.369 3.096 ;
     RECT  6.721 11.184 7.405 16.824 ;
     RECT  6.853 28.464 7.409 28.488 ;
     RECT  7.405 10.32 7.477 16.824 ;
     RECT  6.721 17.856 7.477 20.088 ;
     RECT  7.261 5.04 7.549 9.192 ;
     RECT  7.477 10.32 7.549 20.088 ;
     RECT  7.369 25.536 7.669 26.136 ;
     RECT  7.085 29.952 7.733 30.072 ;
     RECT  7.669 25.056 7.801 26.136 ;
     RECT  7.369 3.072 7.808 3.96 ;
     RECT  7.549 5.04 7.808 20.088 ;
     RECT  6.257 21.072 7.808 21.672 ;
     RECT  6.865 22.896 7.808 23.928 ;
     RECT  7.801 25.056 7.808 26.376 ;
     RECT  7.808 2.148 7.912 28.092 ;
     RECT  7.912 2.418 8.104 27.822 ;
     RECT  8.104 9.264 8.201 11.832 ;
     RECT  8.104 17.184 8.243 20.088 ;
     RECT  8.104 21.216 8.489 21.48 ;
     RECT  8.104 5.04 8.597 7.944 ;
     RECT  8.201 9.264 8.597 9.384 ;
     RECT  8.104 13.056 8.597 15.336 ;
     RECT  7.733 30.048 8.597 30.072 ;
     RECT  8.243 19.344 8.669 20.088 ;
     RECT  8.597 5.04 8.741 7.464 ;
     RECT  8.741 6.72 8.813 7.464 ;
     RECT  8.597 9.264 8.957 9.288 ;
     RECT  8.104 2.496 9.097 3.096 ;
     RECT  8.104 23.616 9.097 24.504 ;
     RECT  8.489 21.216 9.173 21.432 ;
     RECT  9.097 23.328 9.205 24.504 ;
     RECT  8.104 25.536 9.205 25.56 ;
     RECT  8.104 26.592 9.205 26.664 ;
     RECT  9.205 25.536 9.209 26.664 ;
     RECT  8.201 10.56 9.313 11.832 ;
     RECT  8.243 17.184 9.313 17.976 ;
     RECT  9.313 10.512 9.349 11.832 ;
     RECT  8.669 19.344 9.353 20.04 ;
     RECT  9.173 21.408 9.389 21.432 ;
     RECT  9.349 10.416 9.445 11.832 ;
     RECT  8.597 13.056 9.445 15.288 ;
     RECT  9.209 26.256 9.457 26.664 ;
     RECT  9.313 16.608 9.533 17.976 ;
     RECT  9.097 2.496 9.677 3.432 ;
     RECT  9.533 17.232 9.677 17.976 ;
     RECT  9.493 21.6 9.685 21.672 ;
     RECT  9.457 26.256 9.713 26.904 ;
     RECT  8.813 6.768 9.781 7.464 ;
     RECT  9.205 8.448 9.781 9.144 ;
     RECT  8.741 5.04 9.889 5.736 ;
     RECT  9.445 10.416 9.997 15.288 ;
     RECT  9.205 22.752 10.001 24.504 ;
     RECT  9.781 6.768 10.117 9.144 ;
     RECT  9.997 10.32 10.117 15.288 ;
     RECT  10.001 24.384 10.249 24.504 ;
     RECT  10.117 6.768 10.325 15.288 ;
     RECT  9.889 4.224 10.357 5.736 ;
     RECT  10.325 6.768 10.357 13.56 ;
     RECT  10.357 4.224 10.433 13.56 ;
     RECT  10.325 14.64 10.433 15.288 ;
     RECT  9.677 17.664 10.537 17.976 ;
     RECT  9.713 26.256 10.577 26.664 ;
     RECT  10.433 14.832 10.609 15.288 ;
     RECT  10.249 24.384 10.649 24.936 ;
     RECT  10.609 16.512 10.717 16.536 ;
     RECT  10.537 17.664 10.717 18.456 ;
     RECT  10.717 16.512 10.748 18.456 ;
     RECT  10.433 4.224 10.757 13.416 ;
     RECT  9.353 19.536 10.789 20.04 ;
     RECT  9.685 21.6 10.825 21.768 ;
     RECT  10.001 22.752 10.825 22.92 ;
     RECT  10.748 16.416 10.835 18.456 ;
     RECT  10.577 26.256 10.861 26.28 ;
     RECT  10.609 14.832 10.865 15.336 ;
     RECT  9.677 2.496 10.897 2.52 ;
     RECT  10.789 19.536 10.933 20.328 ;
     RECT  10.757 9.888 10.937 13.416 ;
     RECT  10.897 2.496 11.149 3.192 ;
     RECT  10.757 4.224 11.149 8.28 ;
     RECT  10.649 24.384 11.249 24.504 ;
     RECT  10.825 21.6 11.315 22.92 ;
     RECT  11.249 23.952 11.333 24.504 ;
     RECT  11.315 21.6 11.365 22.824 ;
     RECT  11.333 24.384 11.405 24.504 ;
     RECT  10.835 18.144 11.468 18.456 ;
     RECT  10.937 13.392 11.473 13.416 ;
     RECT  11.473 13.392 11.513 13.848 ;
     RECT  10.865 14.832 11.549 15.288 ;
     RECT  11.365 21.408 11.555 22.824 ;
     RECT  11.473 28.464 11.581 28.488 ;
     RECT  11.555 21.408 11.653 22.056 ;
     RECT  10.937 9.888 11.693 12.408 ;
     RECT  10.861 26.208 11.725 26.28 ;
     RECT  11.405 24.48 11.729 24.504 ;
     RECT  10.933 19.536 11.761 20.376 ;
     RECT  11.653 21.36 11.761 22.056 ;
     RECT  11.468 18.144 11.852 18.552 ;
     RECT  11.761 19.536 11.852 22.056 ;
     RECT  11.693 9.888 11.873 10.872 ;
     RECT  11.581 28.416 11.873 28.488 ;
     RECT  11.873 28.416 11.891 28.44 ;
     RECT  11.149 2.496 11.905 8.28 ;
     RECT  11.873 9.888 11.905 10.728 ;
     RECT  11.852 18.144 11.939 22.056 ;
     RECT  11.905 2.496 11.987 10.728 ;
     RECT  11.987 3.936 11.989 10.728 ;
     RECT  11.939 19.968 12.017 20.328 ;
     RECT  10.835 16.512 12.053 17.064 ;
     RECT  11.797 27.312 12.123 27.336 ;
     RECT  11.725 26.112 12.133 26.28 ;
     RECT  12.123 27.312 12.133 27.384 ;
     RECT  11.401 29.664 12.179 29.688 ;
     RECT  11.939 18.144 12.409 18.888 ;
     RECT  12.517 29.856 12.611 30.024 ;
     RECT  12.133 26.112 12.733 27.384 ;
     RECT  12.611 29.952 12.901 30.024 ;
     RECT  11.513 13.632 13.021 13.848 ;
     RECT  11.549 14.976 13.021 15.288 ;
     RECT  13.021 13.584 13.045 13.848 ;
     RECT  13.021 14.832 13.045 15.288 ;
     RECT  12.409 18.096 13.057 18.888 ;
     RECT  12.017 19.968 13.057 19.992 ;
     RECT  11.693 12.336 13.129 12.408 ;
     RECT  13.045 13.584 13.129 15.288 ;
     RECT  12.053 17.04 13.129 17.064 ;
     RECT  11.987 2.496 13.208 2.568 ;
     RECT  11.989 3.936 13.208 8.472 ;
     RECT  11.989 9.792 13.208 10.728 ;
     RECT  13.129 12.336 13.208 15.288 ;
     RECT  13.129 16.8 13.208 17.064 ;
     RECT  13.057 18.096 13.208 19.992 ;
     RECT  11.939 21.36 13.208 22.056 ;
     RECT  12.805 24.48 13.208 24.504 ;
     RECT  12.733 25.536 13.208 27.384 ;
     RECT  13.208 2.148 13.312 28.092 ;
     RECT  13.312 2.256 13.381 28.092 ;
     RECT  13.381 2.256 13.504 28.2 ;
     RECT  13.504 27.216 13.601 28.2 ;
     RECT  12.901 29.952 13.628 30.12 ;
     RECT  13.601 27.216 13.645 27.336 ;
     RECT  13.628 29.664 13.715 30.12 ;
     RECT  13.504 3.936 13.745 11.736 ;
     RECT  13.504 23.904 13.817 25.704 ;
     RECT  13.645 27.312 13.925 27.336 ;
     RECT  13.745 4.512 14.285 11.736 ;
     RECT  13.504 21.168 14.285 21.672 ;
     RECT  13.504 2.256 14.429 2.904 ;
     RECT  13.715 30 14.465 30.12 ;
     RECT  13.504 22.8 14.473 22.824 ;
     RECT  13.504 17.616 14.677 19.608 ;
     RECT  13.817 25.056 14.713 25.704 ;
     RECT  13.504 13.056 14.725 15.96 ;
     RECT  14.677 17.616 14.817 19.944 ;
     RECT  14.285 4.512 14.821 6.12 ;
     RECT  14.817 18.48 14.825 19.944 ;
     RECT  14.725 13.056 14.857 16.536 ;
     RECT  14.285 7.152 14.917 11.736 ;
     RECT  14.857 13.056 14.917 17.112 ;
     RECT  14.713 25.056 14.929 26.568 ;
     RECT  14.825 18.48 14.933 18.936 ;
     RECT  14.929 25.056 14.933 26.664 ;
     RECT  14.917 7.152 14.963 17.112 ;
     RECT  14.963 7.152 14.969 12.552 ;
     RECT  14.285 21.648 14.969 21.672 ;
     RECT  14.963 13.68 15.004 17.112 ;
     RECT  15.004 13.824 15.011 17.112 ;
     RECT  14.465 30.096 15.011 30.12 ;
     RECT  13.817 23.904 15.037 23.928 ;
     RECT  15.011 13.824 15.077 16.536 ;
     RECT  14.825 19.92 15.145 19.944 ;
     RECT  14.933 25.776 15.149 26.664 ;
     RECT  15.037 23.904 15.329 24.792 ;
     RECT  14.933 18.48 15.437 18.504 ;
     RECT  14.969 7.152 15.473 8.568 ;
     RECT  15.077 14.544 15.473 16.536 ;
     RECT  14.821 4.416 15.757 6.12 ;
     RECT  15.757 3.936 15.761 6.12 ;
     RECT  15.761 5.088 15.781 6.12 ;
     RECT  15.781 5.088 15.827 6.648 ;
     RECT  15.827 5.184 15.868 6.648 ;
     RECT  14.429 2.256 15.925 2.28 ;
     RECT  15.761 3.936 15.925 3.96 ;
     RECT  15.925 2.256 15.971 3.96 ;
     RECT  15.971 2.448 16.012 3.96 ;
     RECT  15.868 5.184 16.013 6.12 ;
     RECT  15.329 24.048 16.013 24.792 ;
     RECT  15.973 29.664 16.115 29.688 ;
     RECT  15.325 22.176 16.117 22.2 ;
     RECT  16.013 24.048 16.163 24.072 ;
     RECT  14.969 12.384 16.193 12.552 ;
     RECT  15.149 25.776 16.297 26.28 ;
     RECT  16.297 25.776 16.333 26.808 ;
     RECT  15.361 27.888 16.333 27.912 ;
     RECT  15.901 18.384 16.357 18.408 ;
     RECT  16.013 5.52 16.373 6.12 ;
     RECT  16.357 17.568 16.445 18.408 ;
     RECT  15.473 14.688 16.464 16.536 ;
     RECT  16.012 2.448 16.553 2.472 ;
     RECT  15.145 19.92 16.553 20.04 ;
     RECT  16.333 25.776 16.621 27.912 ;
     RECT  14.969 9.648 16.625 11.352 ;
     RECT  16.193 12.384 16.661 12.408 ;
     RECT  15.473 7.872 16.729 8.568 ;
     RECT  16.625 9.792 16.729 11.352 ;
     RECT  16.464 14.688 16.765 16.008 ;
     RECT  16.729 7.392 16.805 8.568 ;
     RECT  16.621 25.68 16.835 27.912 ;
     RECT  16.805 7.392 16.876 8.52 ;
     RECT  16.445 18.144 17.084 18.408 ;
     RECT  16.765 13.872 17.093 16.008 ;
     RECT  16.876 7.44 17.129 8.52 ;
     RECT  17.093 15.696 17.171 16.008 ;
     RECT  17.084 18.144 17.171 19.368 ;
     RECT  17.171 15.984 17.173 16.008 ;
     RECT  16.373 5.52 17.237 5.736 ;
     RECT  16.729 20.496 17.381 20.52 ;
     RECT  16.012 3.936 17.449 3.96 ;
     RECT  17.237 5.712 17.449 5.736 ;
     RECT  16.117 22.176 17.485 22.872 ;
     RECT  16.835 25.68 17.653 27.384 ;
     RECT  16.729 9.792 17.701 11.928 ;
     RECT  17.701 9.792 17.737 12.648 ;
     RECT  17.485 21.744 17.749 22.872 ;
     RECT  17.737 9.792 17.773 12.888 ;
     RECT  17.809 20.592 17.845 20.616 ;
     RECT  17.749 21.744 17.845 23.352 ;
     RECT  17.665 16.08 17.917 16.104 ;
     RECT  17.449 5.712 18.097 6.12 ;
     RECT  17.773 9.36 18.097 12.888 ;
     RECT  17.093 13.872 18.097 14.712 ;
     RECT  17.129 7.44 18.14 7.896 ;
     RECT  17.653 24.864 18.493 27.384 ;
     RECT  17.449 3.936 18.608 4.296 ;
     RECT  18.097 5.712 18.608 6.36 ;
     RECT  18.14 7.44 18.608 8.376 ;
     RECT  18.097 9.36 18.608 14.712 ;
     RECT  17.917 16.08 18.608 16.536 ;
     RECT  17.171 18.144 18.608 19.032 ;
     RECT  17.845 20.592 18.608 23.352 ;
     RECT  18.493 24.576 18.608 27.384 ;
     RECT  18.608 2.148 18.712 28.092 ;
     RECT  18.712 2.418 18.904 27.822 ;
     RECT  18.904 4.128 19.037 4.152 ;
     RECT  18.904 5.184 19.145 11.736 ;
     RECT  18.904 24.48 19.253 26.136 ;
     RECT  18.904 16.368 19.577 19.416 ;
     RECT  19.145 5.184 19.612 5.736 ;
     RECT  18.904 23.376 19.757 23.4 ;
     RECT  18.904 12.768 19.829 15.192 ;
     RECT  19.612 5.184 19.897 5.592 ;
     RECT  19.897 4.512 19.981 5.592 ;
     RECT  19.577 16.752 20.003 19.416 ;
     RECT  20.003 17.568 20.051 19.416 ;
     RECT  20.051 17.568 20.081 17.88 ;
     RECT  18.904 22.08 20.153 22.344 ;
     RECT  18.904 20.592 20.252 20.76 ;
     RECT  19.145 7.2 20.261 11.736 ;
     RECT  20.252 20.496 20.293 20.76 ;
     RECT  19.829 13.872 20.333 15.192 ;
     RECT  20.293 20.496 20.339 21.144 ;
     RECT  20.261 7.2 20.501 11.688 ;
     RECT  20.051 19.248 20.549 19.272 ;
     RECT  20.509 3.936 20.593 3.96 ;
     RECT  19.981 5.04 20.62 5.592 ;
     RECT  20.501 6.576 20.621 11.688 ;
     RECT  20.339 20.736 20.621 21.144 ;
     RECT  19.253 24.48 20.689 25.992 ;
     RECT  20.621 21.12 20.693 21.144 ;
     RECT  20.153 22.32 20.797 22.344 ;
     RECT  20.689 24.432 20.828 25.992 ;
     RECT  20.437 27.6 20.828 27.624 ;
     RECT  20.621 10.176 20.837 11.688 ;
     RECT  20.797 22.32 20.905 22.488 ;
     RECT  20.828 24.432 20.915 27.624 ;
     RECT  20.621 6.576 21.053 9.048 ;
     RECT  20.081 17.616 21.157 17.88 ;
     RECT  20.62 5.04 21.161 5.064 ;
     RECT  21.053 6.816 21.269 9.048 ;
     RECT  20.905 22.32 21.301 22.728 ;
     RECT  20.915 24.432 21.305 25.992 ;
     RECT  21.301 22.176 21.397 22.776 ;
     RECT  21.305 24.432 21.397 25.752 ;
     RECT  21.397 22.176 21.443 25.752 ;
     RECT  21.443 22.176 21.485 24.504 ;
     RECT  21.485 22.176 21.521 23.352 ;
     RECT  20.915 26.976 21.557 27.624 ;
     RECT  20.333 13.872 21.625 14.808 ;
     RECT  21.625 13.872 21.809 15.48 ;
     RECT  21.485 24.432 21.809 24.504 ;
     RECT  20.837 10.8 21.881 11.688 ;
     RECT  21.521 22.464 21.881 23.352 ;
     RECT  21.269 9.024 21.989 9.048 ;
     RECT  21.881 10.8 22.025 10.968 ;
     RECT  21.265 19.392 22.025 19.416 ;
     RECT  22.021 9.552 22.057 9.576 ;
     RECT  19.829 12.768 22.129 12.888 ;
     RECT  21.157 17.088 22.165 17.88 ;
     RECT  21.269 6.816 22.309 7.896 ;
     RECT  21.809 14.784 22.309 15.48 ;
     RECT  22.309 14.784 22.313 15.672 ;
     RECT  22.129 12.192 22.381 12.888 ;
     RECT  22.313 15.456 22.489 15.672 ;
     RECT  22.489 15.456 22.529 15.864 ;
     RECT  21.443 25.728 22.597 25.752 ;
     RECT  21.557 26.976 22.597 27.384 ;
     RECT  21.881 22.464 22.637 22.728 ;
     RECT  22.309 6.816 22.781 8.52 ;
     RECT  22.381 12.192 22.853 13.704 ;
     RECT  22.781 6.816 22.889 6.84 ;
     RECT  22.597 25.728 22.889 27.384 ;
     RECT  22.853 12.192 22.892 12.888 ;
     RECT  21.809 24.48 22.921 24.504 ;
     RECT  22.892 11.664 23.029 12.888 ;
     RECT  22.781 7.968 23.125 8.52 ;
     RECT  22.057 9.552 23.125 10.488 ;
     RECT  22.921 24.48 23.125 24.6 ;
     RECT  22.889 25.728 23.125 25.752 ;
     RECT  22.529 15.552 23.353 15.864 ;
     RECT  22.637 22.656 23.365 22.728 ;
     RECT  22.165 17.088 23.533 18.504 ;
     RECT  23.533 17.088 23.564 18.792 ;
     RECT  23.564 17.088 23.605 18.84 ;
     RECT  23.353 15.552 23.785 16.008 ;
     RECT  23.125 7.968 24.008 10.488 ;
     RECT  23.029 11.472 24.008 12.888 ;
     RECT  23.785 15.264 24.008 16.008 ;
     RECT  23.605 17.088 24.008 19.368 ;
     RECT  23.365 20.496 24.008 21.576 ;
     RECT  23.365 22.656 24.008 23.064 ;
     RECT  23.125 24.48 24.008 25.752 ;
     RECT  22.889 26.88 24.008 27.384 ;
     RECT  24.008 2.148 24.112 28.092 ;
     RECT  24.112 2.418 24.304 27.822 ;
     RECT  24.304 7.44 24.581 13.08 ;
     RECT  24.304 15.264 24.581 18.84 ;
     RECT  24.304 24.624 24.707 24.648 ;
     RECT  24.581 7.44 24.725 11.544 ;
     RECT  24.581 17.088 24.753 18.84 ;
     RECT  24.725 7.44 24.869 11.496 ;
     RECT  24.869 7.44 24.995 11.4 ;
     RECT  24.581 12.864 25.049 13.08 ;
     RECT  24.995 10.992 25.121 11.4 ;
     RECT  24.581 15.264 25.229 16.056 ;
     RECT  24.753 18.528 25.229 18.84 ;
     RECT  24.304 20.928 25.429 21.288 ;
     RECT  24.304 22.752 25.429 23.016 ;
     RECT  25.121 11.28 25.445 11.4 ;
     RECT  24.995 7.44 25.481 9.528 ;
     RECT  24.753 17.088 25.517 17.112 ;
     RECT  25.429 20.928 25.585 23.016 ;
     RECT  25.229 18.528 25.589 18.696 ;
     RECT  25.585 20.4 25.769 23.016 ;
     RECT  24.304 26.496 25.945 26.52 ;
     RECT  25.229 15.264 26.021 15.912 ;
     RECT  25.769 20.4 26.021 22.68 ;
     RECT  25.945 25.68 26.021 26.52 ;
     RECT  25.049 12.864 26.201 12.888 ;
     RECT  26.161 11.856 26.413 11.88 ;
     RECT  26.021 22.224 26.453 22.68 ;
     RECT  25.481 8.544 26.489 9.528 ;
     RECT  25.589 18.528 26.525 18.552 ;
     RECT  26.021 15.888 26.561 15.912 ;
     RECT  26.021 20.4 26.561 20.472 ;
     RECT  26.021 25.68 26.633 25.704 ;
     RECT  26.489 8.544 26.669 8.568 ;
     RECT  24.304 14.208 26.669 14.232 ;
     RECT  26.413 11.76 26.813 11.88 ;
     RECT  26.813 11.76 26.885 11.784 ;
     RECT  26.453 22.224 26.957 22.248 ;
     RECT  26.561 20.448 27.389 20.472 ;
     RECT  29.653 7.536 30.204 7.56 ;
    LAYER M5 ;
     RECT  2.4 2.137 2.52 2.151 ;
     RECT  7.8 2.137 7.92 2.151 ;
     RECT  13.2 2.137 13.32 2.151 ;
     RECT  18.6 2.137 18.72 2.151 ;
     RECT  24 2.137 24.12 2.151 ;
     RECT  15.936 2.245 15.96 3.971 ;
     RECT  18.6 2.151 18.912 4.261 ;
     RECT  20.544 3.925 20.568 4.501 ;
     RECT  18.192 4.261 18.912 5.173 ;
     RECT  19.92 4.501 20.568 5.173 ;
     RECT  18.192 5.173 20.568 5.219 ;
     RECT  11.952 3.205 11.976 5.221 ;
     RECT  13.2 2.151 13.512 5.221 ;
     RECT  18.192 5.219 19.56 5.747 ;
     RECT  11.952 5.221 13.512 6.275 ;
     RECT  20.544 5.219 20.568 6.611 ;
     RECT  15.792 5.077 15.816 6.659 ;
     RECT  5.088 4.261 5.112 6.805 ;
     RECT  2.4 2.151 2.712 6.853 ;
     RECT  5.04 6.805 5.112 7.381 ;
     RECT  4.8 7.381 5.112 7.427 ;
     RECT  7.8 2.151 8.112 7.429 ;
     RECT  4.8 7.427 5.064 7.523 ;
     RECT  13.2 6.275 13.512 7.669 ;
     RECT  13.104 7.669 13.512 7.859 ;
     RECT  16.8 7.381 16.824 7.907 ;
     RECT  24 2.151 24.312 7.957 ;
     RECT  2.4 6.853 3.432 8.003 ;
     RECT  20.496 7.189 20.52 8.003 ;
     RECT  7.68 7.429 8.112 8.195 ;
     RECT  13.2 7.859 13.512 8.677 ;
     RECT  23.136 7.957 24.312 8.821 ;
     RECT  13.2 8.677 13.608 9.011 ;
     RECT  11.952 6.275 11.976 9.155 ;
     RECT  23.136 8.821 24.984 9.923 ;
     RECT  10.128 9.109 10.152 9.925 ;
     RECT  24 9.923 24.984 10.211 ;
     RECT  18.192 5.747 18.912 10.261 ;
     RECT  20.544 9.013 20.568 10.261 ;
     RECT  2.4 8.003 2.712 10.453 ;
     RECT  10.128 9.925 10.68 10.693 ;
     RECT  18.192 10.261 20.568 10.979 ;
     RECT  7.8 8.195 8.112 11.173 ;
     RECT  9.456 10.693 10.68 11.173 ;
     RECT  16.848 9.925 16.872 11.459 ;
     RECT  2.4 10.453 3.528 11.507 ;
     RECT  9.12 11.173 10.68 11.507 ;
     RECT  7.68 11.173 8.112 11.699 ;
     RECT  9.12 11.507 9.48 11.699 ;
     RECT  18.192 10.979 19.8 11.699 ;
     RECT  22.944 10.453 22.968 11.699 ;
     RECT  10.464 11.507 10.68 12.035 ;
     RECT  10.464 12.035 10.488 12.083 ;
     RECT  9.456 11.699 9.48 12.227 ;
     RECT  18.192 11.699 18.912 12.803 ;
     RECT  9.504 12.517 9.528 13.235 ;
     RECT  4.8 7.523 4.824 13.331 ;
     RECT  13.2 9.011 13.512 13.621 ;
     RECT  14.928 12.517 14.952 13.715 ;
     RECT  13.056 13.621 13.512 15.205 ;
     RECT  24 10.211 24.312 15.301 ;
     RECT  15.36 14.677 15.384 15.443 ;
     RECT  6.672 14.437 6.696 15.493 ;
     RECT  6.288 15.493 6.696 15.539 ;
     RECT  2.4 11.507 2.712 15.685 ;
     RECT  17.136 14.197 17.16 16.019 ;
     RECT  24 15.301 25.032 16.019 ;
     RECT  2.304 15.685 2.712 16.357 ;
     RECT  9.936 13.285 9.96 16.405 ;
     RECT  11.52 15.061 11.544 16.405 ;
     RECT  0.144 16.261 0.168 16.451 ;
     RECT  12.816 15.205 13.512 17.075 ;
     RECT  14.736 15.925 14.76 17.077 ;
     RECT  2.304 16.357 2.856 17.411 ;
     RECT  7.8 11.699 8.112 17.605 ;
     RECT  14.736 17.077 15 17.651 ;
     RECT  19.968 12.757 19.992 17.653 ;
     RECT  6.288 15.539 6.312 17.699 ;
     RECT  24 16.019 24.312 17.845 ;
     RECT  2.304 17.411 2.808 17.939 ;
     RECT  23.904 17.845 24.312 17.941 ;
     RECT  3.984 17.029 4.008 18.037 ;
     RECT  2.4 17.939 2.808 18.275 ;
     RECT  16.368 16.501 16.392 18.419 ;
     RECT  3.984 18.037 4.824 18.467 ;
     RECT  9.936 16.405 11.544 18.467 ;
     RECT  13.2 17.075 13.512 18.757 ;
     RECT  14.976 17.651 15 18.757 ;
     RECT  23.904 17.941 24.696 18.805 ;
     RECT  19.968 17.653 20.04 18.995 ;
     RECT  11.52 18.467 11.544 19.141 ;
     RECT  23.616 18.805 24.696 19.379 ;
     RECT  7.8 17.605 8.232 19.427 ;
     RECT  20.016 18.995 20.04 19.427 ;
     RECT  13.2 18.757 15 19.523 ;
     RECT  2.4 18.275 2.712 19.909 ;
     RECT  24 19.379 24.696 20.485 ;
     RECT  2.4 19.909 3.432 20.531 ;
     RECT  17.136 19.333 17.16 20.531 ;
     RECT  23.376 20.485 24.696 20.917 ;
     RECT  2.4 20.531 2.808 21.155 ;
     RECT  20.304 20.485 20.328 21.155 ;
     RECT  11.52 19.141 11.928 21.395 ;
     RECT  13.2 19.523 13.512 21.589 ;
     RECT  9.936 18.467 9.96 21.635 ;
     RECT  12.816 21.589 13.512 21.637 ;
     RECT  14.976 19.523 15 21.637 ;
     RECT  23.376 20.917 25.464 21.971 ;
     RECT  11.52 21.395 11.544 22.165 ;
     RECT  11.28 22.165 11.544 22.835 ;
     RECT  12.816 21.637 15 22.835 ;
     RECT  23.376 21.971 24.696 23.075 ;
     RECT  18.6 12.803 18.912 23.317 ;
     RECT  21.504 22.741 21.528 23.363 ;
     RECT  9.696 21.733 9.72 23.891 ;
     RECT  11.28 22.835 11.304 23.987 ;
     RECT  16.128 22.837 16.152 24.083 ;
     RECT  12.816 22.835 13.512 24.421 ;
     RECT  12.816 24.421 13.608 24.515 ;
     RECT  4.8 18.467 4.824 24.563 ;
     RECT  24 23.075 24.696 24.659 ;
     RECT  17.76 23.317 18.912 24.853 ;
     RECT  7.8 19.427 8.112 25.045 ;
     RECT  24 24.659 24.312 25.045 ;
     RECT  21.408 23.653 21.432 25.091 ;
     RECT  7.68 25.045 8.112 25.571 ;
     RECT  5.184 25.285 5.208 25.573 ;
     RECT  14.976 22.835 15 25.669 ;
     RECT  17.664 24.853 18.912 25.715 ;
     RECT  23.136 25.045 24.312 25.763 ;
     RECT  5.136 25.573 5.208 26.389 ;
     RECT  14.784 25.669 15 26.531 ;
     RECT  5.136 26.389 6.12 26.629 ;
     RECT  13.056 24.515 13.608 26.629 ;
     RECT  12.288 26.629 13.608 27.205 ;
     RECT  5.136 26.629 6.168 27.253 ;
     RECT  12.144 27.205 13.608 27.301 ;
     RECT  20.88 26.917 20.904 27.635 ;
     RECT  16.8 26.725 16.824 27.923 ;
     RECT  2.4 21.155 2.712 27.925 ;
     RECT  7.8 25.571 8.112 28.089 ;
     RECT  18.6 25.715 18.912 28.089 ;
     RECT  24 25.763 24.312 28.089 ;
     RECT  2.4 27.925 3.144 28.103 ;
     RECT  7.8 28.089 7.92 28.103 ;
     RECT  18.6 28.089 18.72 28.103 ;
     RECT  24 28.089 24.12 28.103 ;
     RECT  3.12 28.103 3.144 28.405 ;
     RECT  11.952 27.301 13.8 28.405 ;
     RECT  3.12 28.405 3.336 28.453 ;
     RECT  5.136 27.253 6.6 28.453 ;
     RECT  11.856 28.405 13.8 28.453 ;
     RECT  3.12 28.453 3.432 29.077 ;
     RECT  5.136 28.453 6.888 29.605 ;
     RECT  11.664 28.453 13.8 29.653 ;
     RECT  14.976 26.531 15 30.085 ;
     RECT  14.832 30.085 15 30.131 ;
     RECT  3.024 29.077 3.432 30.224 ;
     RECT  4.56 29.605 6.888 30.224 ;
     RECT  11.568 29.653 13.8 30.224 ;
     RECT  14.832 30.131 14.856 30.224 ;
     RECT  16.08 29.653 16.104 30.224 ;
  END
END qfd_res_train_issue
END LIBRARY
